VERSION 5.7 ;
  NOWIREEXTENSIONATPIN ON ;
  DIVIDERCHAR "/" ;
  BUSBITCHARS "[]" ;
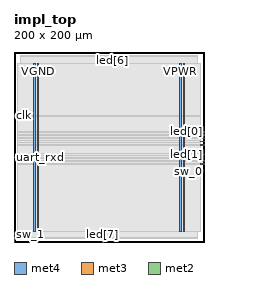
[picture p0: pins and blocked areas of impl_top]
MACRO impl_top
  CLASS BLOCK ;
  FOREIGN impl_top ;
  ORIGIN 0.000 0.000 ;
  SIZE 200.000 BY 200.000 ;
  PIN VGND
    DIRECTION INOUT ;
    USE GROUND ;
    PORT
      LAYER met4 ;
        RECT 24.340 10.640 25.940 187.920 ;
    END
    PORT
      LAYER met4 ;
        RECT 177.940 10.640 179.540 187.920 ;
    END
  END VGND
  PIN VPWR
    DIRECTION INOUT ;
    USE POWER ;
    PORT
      LAYER met4 ;
        RECT 21.040 10.640 22.640 187.920 ;
    END
    PORT
      LAYER met4 ;
        RECT 174.640 10.640 176.240 187.920 ;
    END
  END VPWR
  PIN clk
    DIRECTION INPUT ;
    USE SIGNAL ;
    ANTENNAGATEAREA 1.286700 ;
    ANTENNADIFFAREA 0.434700 ;
    PORT
      LAYER met3 ;
        RECT 0.000 132.640 4.000 133.240 ;
    END
  END clk
  PIN led[0]
    DIRECTION OUTPUT ;
    USE SIGNAL ;
    ANTENNADIFFAREA 0.445500 ;
    PORT
      LAYER met3 ;
        RECT 196.000 115.640 200.000 116.240 ;
    END
  END led[0]
  PIN led[1]
    DIRECTION OUTPUT ;
    USE SIGNAL ;
    ANTENNADIFFAREA 0.445500 ;
    PORT
      LAYER met3 ;
        RECT 196.000 91.840 200.000 92.440 ;
    END
  END led[1]
  PIN led[2]
    DIRECTION OUTPUT ;
    USE SIGNAL ;
    ANTENNADIFFAREA 0.445500 ;
    PORT
      LAYER met3 ;
        RECT 196.000 112.240 200.000 112.840 ;
    END
  END led[2]
  PIN led[3]
    DIRECTION OUTPUT ;
    USE SIGNAL ;
    ANTENNADIFFAREA 0.445500 ;
    PORT
      LAYER met3 ;
        RECT 196.000 102.040 200.000 102.640 ;
    END
  END led[3]
  PIN led[4]
    DIRECTION OUTPUT ;
    USE SIGNAL ;
    ANTENNADIFFAREA 0.445500 ;
    PORT
      LAYER met3 ;
        RECT 196.000 108.840 200.000 109.440 ;
    END
  END led[4]
  PIN led[5]
    DIRECTION OUTPUT ;
    USE SIGNAL ;
    ANTENNADIFFAREA 0.445500 ;
    PORT
      LAYER met3 ;
        RECT 196.000 105.440 200.000 106.040 ;
    END
  END led[5]
  PIN led[6]
    DIRECTION OUTPUT ;
    USE SIGNAL ;
    ANTENNADIFFAREA 0.445500 ;
    PORT
      LAYER met2 ;
        RECT 103.130 196.000 103.410 200.000 ;
    END
  END led[6]
  PIN led[7]
    DIRECTION OUTPUT ;
    USE SIGNAL ;
    ANTENNADIFFAREA 0.445500 ;
    PORT
      LAYER met2 ;
        RECT 93.470 0.000 93.750 4.000 ;
    END
  END led[7]
  PIN sw_0
    DIRECTION INPUT ;
    USE SIGNAL ;
    ANTENNAGATEAREA 0.631200 ;
    ANTENNADIFFAREA 0.434700 ;
    PORT
      LAYER met3 ;
        RECT 196.000 81.640 200.000 82.240 ;
    END
  END sw_0
  PIN sw_1
    DIRECTION INPUT ;
    USE SIGNAL ;
    PORT
      LAYER met2 ;
        RECT 0.090 0.000 0.370 4.000 ;
    END
  END sw_1
  PIN uart_rxd
    DIRECTION INPUT ;
    USE SIGNAL ;
    ANTENNAGATEAREA 0.631200 ;
    ANTENNADIFFAREA 0.434700 ;
    PORT
      LAYER met3 ;
        RECT 0.000 88.440 4.000 89.040 ;
    END
  END uart_rxd
  PIN uart_txd
    DIRECTION OUTPUT ;
    USE SIGNAL ;
    ANTENNADIFFAREA 0.445500 ;
    PORT
      LAYER met3 ;
        RECT 196.000 85.040 200.000 85.640 ;
    END
  END uart_txd
  OBS
      LAYER nwell ;
        RECT 5.330 10.760 194.310 187.870 ;
      LAYER li1 ;
        RECT 5.520 10.795 194.120 187.765 ;
      LAYER met1 ;
        RECT 5.520 10.640 194.420 187.920 ;
      LAYER met2 ;
        RECT 6.530 195.720 102.850 196.000 ;
        RECT 103.690 195.720 192.640 196.000 ;
        RECT 6.530 4.280 192.640 195.720 ;
        RECT 6.530 4.000 93.190 4.280 ;
        RECT 94.030 4.000 192.640 4.280 ;
      LAYER met3 ;
        RECT 4.000 133.640 196.000 187.845 ;
        RECT 4.400 132.240 196.000 133.640 ;
        RECT 4.000 116.640 196.000 132.240 ;
        RECT 4.000 115.240 195.600 116.640 ;
        RECT 4.000 113.240 196.000 115.240 ;
        RECT 4.000 111.840 195.600 113.240 ;
        RECT 4.000 109.840 196.000 111.840 ;
        RECT 4.000 108.440 195.600 109.840 ;
        RECT 4.000 106.440 196.000 108.440 ;
        RECT 4.000 105.040 195.600 106.440 ;
        RECT 4.000 103.040 196.000 105.040 ;
        RECT 4.000 101.640 195.600 103.040 ;
        RECT 4.000 92.840 196.000 101.640 ;
        RECT 4.000 91.440 195.600 92.840 ;
        RECT 4.000 89.440 196.000 91.440 ;
        RECT 4.400 88.040 196.000 89.440 ;
        RECT 4.000 86.040 196.000 88.040 ;
        RECT 4.000 84.640 195.600 86.040 ;
        RECT 4.000 82.640 196.000 84.640 ;
        RECT 4.000 81.240 195.600 82.640 ;
        RECT 4.000 10.715 196.000 81.240 ;
  END
END impl_top
END LIBRARY

